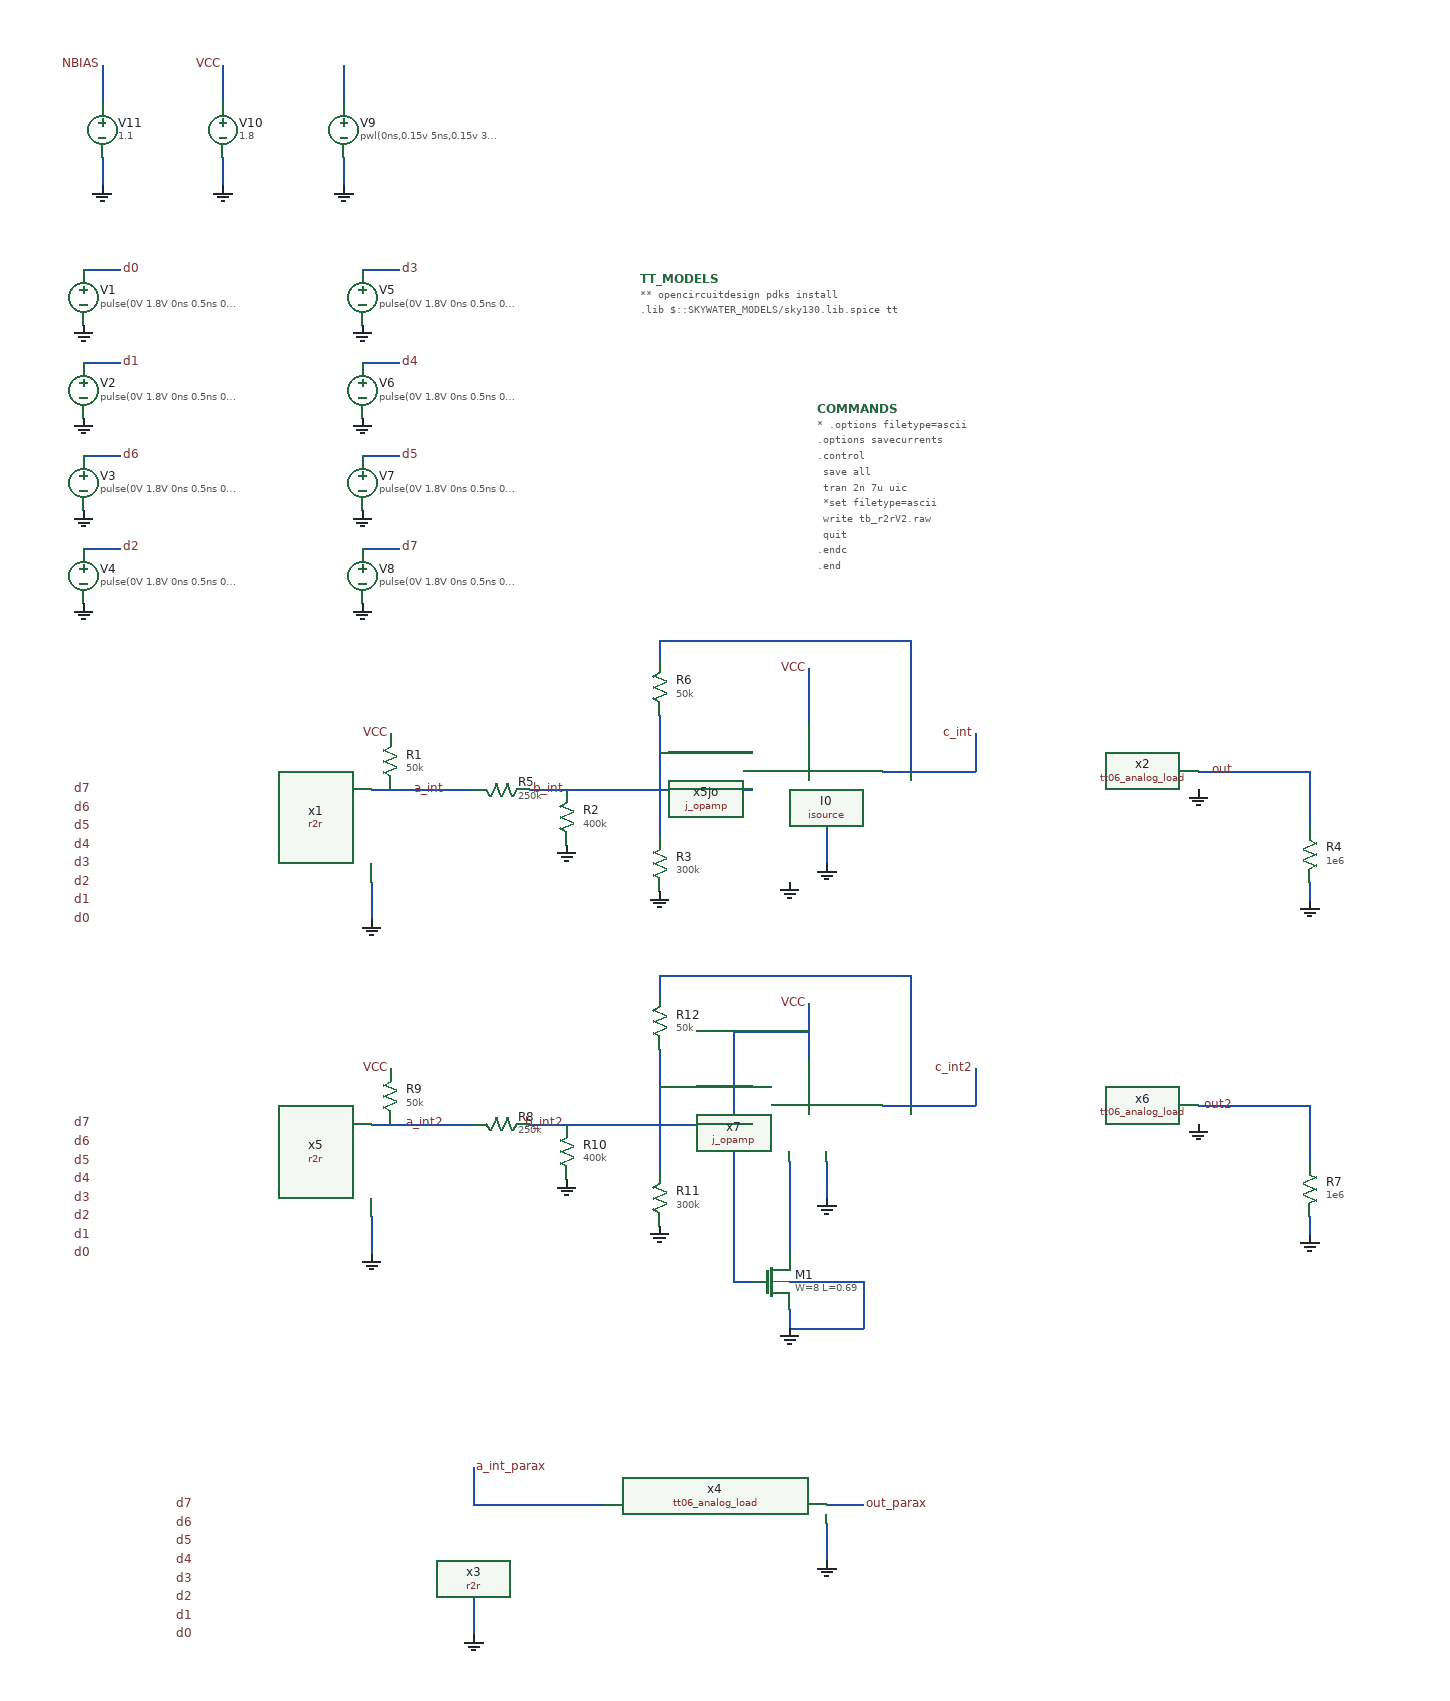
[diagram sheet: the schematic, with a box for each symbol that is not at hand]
v {xschem version=3.4.5 file_version=1.2
}
G {}
K {}
V {}
S {}
E {}
B 2 1490 -880 3030 -180 {flags=graph
y1=7.8e-05
y2=1.8
ypos1=0
ypos2=2
divy=5
subdivy=1
unity=1
x1=5e-12
x2=7e-06
divx=5
subdivx=1
xlabmag=1.0
ylabmag=1.0
node="d1
a_int
c_int
out
a_int2
c_int2
out2"
color="5 21 11 10 8 12 21"
dataset=-1
unitx=1
logx=0
logy=0
}
B 2 1490 -1610 3030 -910 {flags=graph
y1=0
y2=0.0016
ypos1=0
ypos2=2
divy=5
subdivy=1
unity=1
x1=5e-12
x2=7e-06
divx=5
subdivx=1
xlabmag=1.0
ylabmag=1.0


dataset=-1
unitx=1
logx=0
logy=0


rainbow=1























color="8 8 8 8 8 8 12 10 11 16 7 7 7 17 17 17 17 17 17 17 17 17 17 17 17 17 17 17 17 17 21"
node="i(@m.x5jo.xm9.msky130_fd_pr__nfet_01v8[is])
i(@m.x5jo.xm9.msky130_fd_pr__nfet_01v8[ig])
i(@m.x5jo.xm9.msky130_fd_pr__nfet_01v8[id])
i(@m.x5jo.xm9.msky130_fd_pr__nfet_01v8[ib])
i(@m.x5jo.xm8.msky130_fd_pr__pfet_01v8[is])
i(@m.x5jo.xm8.msky130_fd_pr__pfet_01v8[ig])
i(@m.x5jo.xm8.msky130_fd_pr__pfet_01v8[id])
i(@m.x5jo.xm7.msky130_fd_pr__pfet_01v8[id])
i(@m.x5jo.xm6.msky130_fd_pr__nfet_01v8[id])
i(@m.x5jo.xm6.msky130_fd_pr__nfet_01v8[ib])
i(@m.x5jo.xm5.msky130_fd_pr__pfet_01v8[is])
i(@m.x5jo.xm5.msky130_fd_pr__pfet_01v8[ig])
i(@m.x5jo.xm5.msky130_fd_pr__pfet_01v8[id])
i(@m.x5jo.xm5.msky130_fd_pr__pfet_01v8[ib])
i(@m.x5jo.xm4.msky130_fd_pr__nfet_01v8[is])
i(@m.x5jo.xm4.msky130_fd_pr__nfet_01v8[ig])
i(@m.x5jo.xm4.msky130_fd_pr__nfet_01v8[id])
i(@m.x5jo.xm4.msky130_fd_pr__nfet_01v8[ib])
i(@m.x5jo.xm3.msky130_fd_pr__nfet_01v8[is])
i(@m.x5jo.xm3.msky130_fd_pr__nfet_01v8[ig])
i(@m.x5jo.xm3.msky130_fd_pr__nfet_01v8[id])
i(@m.x5jo.xm3.msky130_fd_pr__nfet_01v8[ib])
i(@m.x5jo.xm2.msky130_fd_pr__pfet_01v8[is])
i(@m.x5jo.xm2.msky130_fd_pr__pfet_01v8[ig])
i(@m.x5jo.xm2.msky130_fd_pr__pfet_01v8[id])
i(@m.x5jo.xm2.msky130_fd_pr__pfet_01v8[ib])
i(@m.x5jo.xm1.msky130_fd_pr__pfet_01v8[is])
i(@m.x5jo.xm1.msky130_fd_pr__pfet_01v8[ig])
i(@m.x5jo.xm1.msky130_fd_pr__pfet_01v8[id])
i(@m.x5jo.xm1.msky130_fd_pr__pfet_01v8[ib])
i(@m.xm1.msky130_fd_pr__nfet_01v8[id])"}
N 350 -860 350 -840 {
lab=GND}
N 350 -840 350 -820 {
lab=GND}
N 1240 -980 1280 -980 {
lab=out}
N 40 -1520 80 -1520 {
lab=d0}
N 40 -1420 80 -1420 {
lab=d1}
N 40 -1320 80 -1320 {
lab=d6}
N 40 -1220 80 -1220 {
lab=d2}
N 340 -1520 380 -1520 {
lab=d3}
N 340 -1420 380 -1420 {
lab=d4}
N 340 -1320 380 -1320 {
lab=d5}
N 340 -1220 380 -1220 {
lab=d7}
N 460 -90 460 -70 {
lab=GND}
N 460 -70 460 -50 {
lab=GND}
N 840 -190 880 -190 {
lab=out_parax}
N 460 -230 460 -190 {
lab=a_int_parax}
N 460 -190 480 -190 {
lab=a_int_parax}
N 480 -190 600 -190 {
lab=a_int_parax}
N 840 -170 840 -130 {
lab=GND}
N 190 -1640 190 -1610 {
lab=GND}
N 190 -1740 190 -1700 {
lab=VCC}
N 1360 -860 1360 -840 {
lab=GND}
N 1360 -980 1360 -920 {
lab=out}
N 1000 -1020 1000 -980 {
lab=c_int}
N 350 -960 430 -960 {
lab=a_int}
N 320 -1640 320 -1610 {
lab=GND}
N 320 -1740 320 -1700 {
lab=#net1}
N 430 -960 460 -960 {
lab=a_int}
N 60 -1640 60 -1610 {
lab=GND}
N 60 -1740 60 -1700 {
lab=NBIAS}
N 840 -920 840 -880 {
lab=GND}
N 900 -980 1000 -980 {
lab=c_int}
N 820 -1090 820 -1030 {
lab=VCC}
N 930 -1120 930 -980 {
lab=c_int}
N 720 -1120 930 -1120 {
lab=c_int}
N 660 -1040 660 -910 {
lab=#net2}
N 660 -1120 660 -1100 {
lab=c_int}
N 660 -1120 720 -1120 {
lab=c_int}
N 660 -1000 740 -1000 {
lab=#net2}
N 740 -1000 760 -1000 {
lab=#net2}
N 560 -960 760 -960 {
lab=b_int}
N 520 -960 560 -960 {
lab=b_int}
N 350 -500 350 -480 {
lab=GND}
N 350 -480 350 -460 {
lab=GND}
N 1240 -620 1280 -620 {
lab=out2}
N 1360 -500 1360 -480 {
lab=GND}
N 1360 -620 1360 -560 {
lab=out2}
N 1000 -660 1000 -620 {
lab=c_int2}
N 350 -600 430 -600 {
lab=a_int2}
N 430 -600 460 -600 {
lab=a_int2}
N 840 -560 840 -520 {
lab=GND}
N 900 -620 1000 -620 {
lab=c_int2}
N 820 -730 820 -670 {
lab=VCC}
N 930 -760 930 -620 {
lab=c_int2}
N 720 -760 930 -760 {
lab=c_int2}
N 660 -680 660 -550 {
lab=#net3}
N 660 -760 660 -740 {
lab=c_int2}
N 660 -760 720 -760 {
lab=c_int2}
N 560 -600 760 -600 {
lab=b_int2}
N 520 -600 560 -600 {
lab=b_int2}
N 1280 -980 1360 -980 {
lab=out}
N 1280 -620 1360 -620 {
lab=out2}
N 800 -400 800 -380 {
lab=GND}
N 800 -560 800 -460 {
lab=#net4}
N 800 -430 880 -430 {
lab=GND}
N 880 -430 880 -380 {
lab=GND}
N 800 -380 880 -380 {
lab=GND}
N 740 -430 760 -430 {
lab=VCC}
N 740 -700 820 -700 {
lab=VCC}
N 660 -640 760 -640 {
lab=#net3}
N 740 -700 740 -430 {
lab=VCC}
C {devices/code.sym} 640 -1510 0 0 {name=TT_MODELS
only_toplevel=true
format="tcleval( @value )"
value="
** opencircuitdesign pdks install
.lib $::SKYWATER_MODELS/sky130.lib.spice tt

"
spice_ignore=false}
C {devices/launcher.sym} 840 -1500 0 0 {name=h17 
descr="Load waves" 
tclcommand="
xschem raw_read $netlist_dir/[file tail [file rootname [xschem get current_name]]].raw tran

"
}
C {r2r.sym} 200 -890 0 0 {name=x1}
C {devices/gnd.sym} 350 -820 0 0 {name=l1 lab=GND}
C {tt06_analog_load.sym} 1090 -960 0 0 {name=x2}
C {devices/gnd.sym} 1240 -960 0 0 {name=l2 lab=GND}
C {devices/lab_pin.sym} 1280 -980 1 0 {name=p1 sig_type=std_logic lab=out}
C {devices/vsource.sym} 40 -1490 0 0 {name=V1 value="pulse(0V 1.8V 0ns 0.5ns 0.5ns 20ns 40ns)" savecurrent=false}
C {devices/lab_pin.sym} 80 -1520 2 0 {name=p2 sig_type=std_logic lab=d0}
C {devices/gnd.sym} 40 -1460 0 0 {name=l3 lab=GND}
C {devices/vsource.sym} 40 -1390 0 0 {name=V2 value="pulse(0V 1.8V 0ns 0.5ns 0.5ns 40ns 80ns)" savecurrent=false}
C {devices/lab_pin.sym} 80 -1420 2 0 {name=p3 sig_type=std_logic lab=d1}
C {devices/gnd.sym} 40 -1360 0 0 {name=l4 lab=GND}
C {devices/vsource.sym} 40 -1290 0 0 {name=V3 value="pulse(0V 1.8V 0ns 0.5ns 0.5ns 80ns 160ns)" savecurrent=false}
C {devices/lab_pin.sym} 80 -1320 2 0 {name=p4 sig_type=std_logic lab=d6}
C {devices/gnd.sym} 40 -1260 0 0 {name=l5 lab=GND}
C {devices/vsource.sym} 40 -1190 0 0 {name=V4 value="pulse(0V 1.8V 0ns 0.5ns 0.5ns 160ns 320ns)" savecurrent=false}
C {devices/lab_pin.sym} 80 -1220 2 0 {name=p5 sig_type=std_logic lab=d2}
C {devices/gnd.sym} 40 -1160 0 0 {name=l6 lab=GND}
C {devices/vsource.sym} 340 -1490 0 0 {name=V5 value="pulse(0V 1.8V 0ns 0.5ns 0.5ns 320ns 640ns)" savecurrent=false}
C {devices/lab_pin.sym} 380 -1520 2 0 {name=p6 sig_type=std_logic lab=d3}
C {devices/gnd.sym} 340 -1460 0 0 {name=l7 lab=GND}
C {devices/vsource.sym} 340 -1390 0 0 {name=V6 value="pulse(0V 1.8V 0ns 0.5ns 0.5ns 640ns 1280ns)" savecurrent=false}
C {devices/lab_pin.sym} 380 -1420 2 0 {name=p7 sig_type=std_logic lab=d4}
C {devices/gnd.sym} 340 -1360 0 0 {name=l8 lab=GND}
C {devices/vsource.sym} 340 -1290 0 0 {name=V7 value="pulse(0V 1.8V 0ns 0.5ns 0.5ns 1280ns 2560ns)" savecurrent=false}
C {devices/lab_pin.sym} 380 -1320 2 0 {name=p8 sig_type=std_logic lab=d5}
C {devices/gnd.sym} 340 -1260 0 0 {name=l9 lab=GND}
C {devices/vsource.sym} 340 -1190 0 0 {name=V8 value="pulse(0V 1.8V 0ns 0.5ns 0.5ns 2560ns 5120ns)" savecurrent=false}
C {devices/lab_pin.sym} 380 -1220 2 0 {name=p9 sig_type=std_logic lab=d7}
C {devices/gnd.sym} 340 -1160 0 0 {name=l10 lab=GND}
C {devices/lab_pin.sym} 50 -820 0 0 {name=p10 sig_type=std_logic lab=d0}
C {devices/lab_pin.sym} 50 -840 0 0 {name=p11 sig_type=std_logic lab=d1}
C {devices/lab_pin.sym} 50 -860 0 0 {name=p12 sig_type=std_logic lab=d2}
C {devices/lab_pin.sym} 50 -880 0 0 {name=p13 sig_type=std_logic lab=d3}
C {devices/lab_pin.sym} 50 -900 0 0 {name=p14 sig_type=std_logic lab=d4}
C {devices/lab_pin.sym} 50 -920 0 0 {name=p15 sig_type=std_logic lab=d5}
C {devices/lab_pin.sym} 50 -940 0 0 {name=p16 sig_type=std_logic lab=d6}
C {devices/lab_pin.sym} 50 -960 0 0 {name=p17 sig_type=std_logic lab=d7}
C {devices/simulator_commands_shown.sym} 830 -1370 0 0 {name=COMMANDS
simulator=ngspice
only_toplevel=false 
value="
* .options filetype=ascii
.options savecurrents
.control
  save all
  tran 2n 7u uic
  *set filetype=ascii
  write tb_r2rV2.raw
  quit
.endc
.end
"}
C {r2r.sym} 310 -120 0 0 {name=x3
schematic=r2r_parax.sim
spice_sym_def="tcleval(.include [file normalize ../mag/r2r.sim.spice])"
tclcommand="textwindow          [file normalize ../mag/r2r.sim.spice]"
}
C {devices/gnd.sym} 460 -50 0 0 {name=l11 lab=GND}
C {tt06_analog_load.sym} 690 -170 0 0 {name=x4}
C {devices/lab_pin.sym} 880 -190 2 0 {name=p19 sig_type=std_logic lab=out_parax}
C {devices/lab_pin.sym} 160 -50 0 0 {name=p20 sig_type=std_logic lab=d0}
C {devices/lab_pin.sym} 160 -70 0 0 {name=p21 sig_type=std_logic lab=d1}
C {devices/lab_pin.sym} 160 -90 0 0 {name=p22 sig_type=std_logic lab=d2}
C {devices/lab_pin.sym} 160 -110 0 0 {name=p23 sig_type=std_logic lab=d3}
C {devices/lab_pin.sym} 160 -130 0 0 {name=p24 sig_type=std_logic lab=d4}
C {devices/lab_pin.sym} 160 -150 0 0 {name=p25 sig_type=std_logic lab=d5}
C {devices/lab_pin.sym} 160 -170 0 0 {name=p26 sig_type=std_logic lab=d6}
C {devices/lab_pin.sym} 160 -190 0 0 {name=p27 sig_type=std_logic lab=d7}
C {devices/lab_pin.sym} 460 -230 2 0 {name=p28 sig_type=std_logic lab=a_int_parax}
C {devices/gnd.sym} 840 -130 0 0 {name=l14 lab=GND}
C {devices/vsource.sym} 190 -1670 0 0 {name=V10 value=1.8 savecurrent=false}
C {devices/gnd.sym} 190 -1610 0 0 {name=l15 lab=GND}
C {devices/lab_pin.sym} 190 -1740 0 0 {name=p30 sig_type=std_logic lab=VCC}
C {devices/res.sym} 1360 -890 0 0 {name=R4
value=1e6
footprint=1206
device=resistor
m=1}
C {devices/gnd.sym} 1360 -840 0 0 {name=l13 lab=GND}
C {devices/lab_pin.sym} 560 -960 1 0 {name=p32 sig_type=std_logic lab=b_int}
C {devices/vsource.sym} 320 -1670 0 0 {name=V9
vlo=0
vhi=1.8
value="pwl(0ns,0.15v 5ns,0.15v 3us,0.85v 3.002us,0.15v 3.15us,0.15v 3.152us,0.85v 6us,0.15v 7us,0.15v)" savecurrent=false}
C {devices/gnd.sym} 320 -1610 0 0 {name=l16 lab=GND}
C {devices/lab_pin.sym} 430 -960 1 0 {name=p34 sig_type=std_logic lab=a_int}
C {devices/res.sym} 490 -960 1 0 {name=R5
value=250k
footprint=1206
device=resistor
m=1}
C {devices/vsource.sym} 60 -1670 0 0 {name=V11 value=1.1 savecurrent=false}
C {devices/gnd.sym} 60 -1610 0 0 {name=l12 lab=GND}
C {devices/lab_pin.sym} 60 -1740 0 0 {name=p18 sig_type=std_logic lab=NBIAS}
C {devices/gnd.sym} 840 -880 0 0 {name=l17 lab=GND}
C {devices/lab_pin.sym} 820 -1090 0 0 {name=p29 sig_type=std_logic lab=VCC}
C {devices/res.sym} 370 -990 2 0 {name=R1
value=50k
footprint=1206
device=resistor
m=1}
C {devices/lab_pin.sym} 370 -1020 0 0 {name=p31 sig_type=std_logic lab=VCC}
C {devices/res.sym} 560 -930 2 0 {name=R2
value=400k
footprint=1206
device=resistor
m=1}
C {devices/gnd.sym} 560 -900 0 0 {name=l18 lab=GND}
C {devices/lab_pin.sym} 1000 -1020 0 0 {name=p35 sig_type=std_logic lab=c_int}
C {j_opamp.sym} 830 -980 0 0 {name=x5jo}
C {devices/isource.sym} 800 -890 0 1 {name=I0 value=150u}
C {devices/gnd.sym} 800 -860 0 0 {name=l19 lab=GND}
C {devices/res.sym} 660 -880 2 0 {name=R3
value=300k
footprint=1206
device=resistor
m=1}
C {devices/gnd.sym} 660 -850 0 0 {name=l20 lab=GND}
C {devices/res.sym} 660 -1070 2 0 {name=R6
value=50k
footprint=1206
device=resistor
m=1}
C {r2r.sym} 200 -530 0 0 {name=x5}
C {devices/gnd.sym} 350 -460 0 0 {name=l21 lab=GND}
C {tt06_analog_load.sym} 1090 -600 0 0 {name=x6}
C {devices/gnd.sym} 1240 -600 0 0 {name=l22 lab=GND}
C {devices/lab_pin.sym} 1280 -620 1 0 {name=p33 sig_type=std_logic lab=out2}
C {devices/lab_pin.sym} 50 -460 0 0 {name=p36 sig_type=std_logic lab=d0}
C {devices/lab_pin.sym} 50 -480 0 0 {name=p37 sig_type=std_logic lab=d1}
C {devices/lab_pin.sym} 50 -500 0 0 {name=p38 sig_type=std_logic lab=d2}
C {devices/lab_pin.sym} 50 -520 0 0 {name=p39 sig_type=std_logic lab=d3}
C {devices/lab_pin.sym} 50 -540 0 0 {name=p40 sig_type=std_logic lab=d4}
C {devices/lab_pin.sym} 50 -560 0 0 {name=p41 sig_type=std_logic lab=d5}
C {devices/lab_pin.sym} 50 -580 0 0 {name=p42 sig_type=std_logic lab=d6}
C {devices/lab_pin.sym} 50 -600 0 0 {name=p43 sig_type=std_logic lab=d7}
C {devices/res.sym} 1360 -530 0 0 {name=R7
value=1e6
footprint=1206
device=resistor
m=1}
C {devices/gnd.sym} 1360 -480 0 0 {name=l23 lab=GND}
C {devices/lab_pin.sym} 560 -600 1 0 {name=p44 sig_type=std_logic lab=b_int2}
C {devices/lab_pin.sym} 430 -600 1 0 {name=p45 sig_type=std_logic lab=a_int2}
C {devices/res.sym} 490 -600 1 0 {name=R8
value=250k
footprint=1206
device=resistor
m=1}
C {devices/gnd.sym} 840 -520 0 0 {name=l24 lab=GND}
C {devices/lab_pin.sym} 820 -730 0 0 {name=p46 sig_type=std_logic lab=VCC}
C {devices/res.sym} 370 -630 2 0 {name=R9
value=50k
footprint=1206
device=resistor
m=1}
C {devices/lab_pin.sym} 370 -660 0 0 {name=p47 sig_type=std_logic lab=VCC}
C {devices/res.sym} 560 -570 2 0 {name=R10
value=400k
footprint=1206
device=resistor
m=1}
C {devices/gnd.sym} 560 -540 0 0 {name=l25 lab=GND}
C {devices/lab_pin.sym} 1000 -660 0 0 {name=p48 sig_type=std_logic lab=c_int2}
C {j_opamp.sym} 830 -620 0 0 {name=x7}
C {devices/gnd.sym} 800 -380 0 0 {name=l26 lab=GND}
C {devices/res.sym} 660 -520 2 0 {name=R11
value=300k
footprint=1206
device=resistor
m=1}
C {devices/gnd.sym} 660 -490 0 0 {name=l27 lab=GND}
C {devices/res.sym} 660 -710 2 0 {name=R12
value=50k
footprint=1206
device=resistor
m=1}
C {sky130_fd_pr/nfet_01v8.sym} 780 -430 0 0 {name=M1
L=0.69
W=8
nf=1 
mult=1
ad="'int((nf+1)/2) * W/nf * 0.29'" 
pd="'2*int((nf+1)/2) * (W/nf + 0.29)'"
as="'int((nf+2)/2) * W/nf * 0.29'" 
ps="'2*int((nf+2)/2) * (W/nf + 0.29)'"
nrd="'0.29 / W'" nrs="'0.29 / W'"
sa=0 sb=0 sd=0
model=nfet_01v8
spiceprefix=X
}
